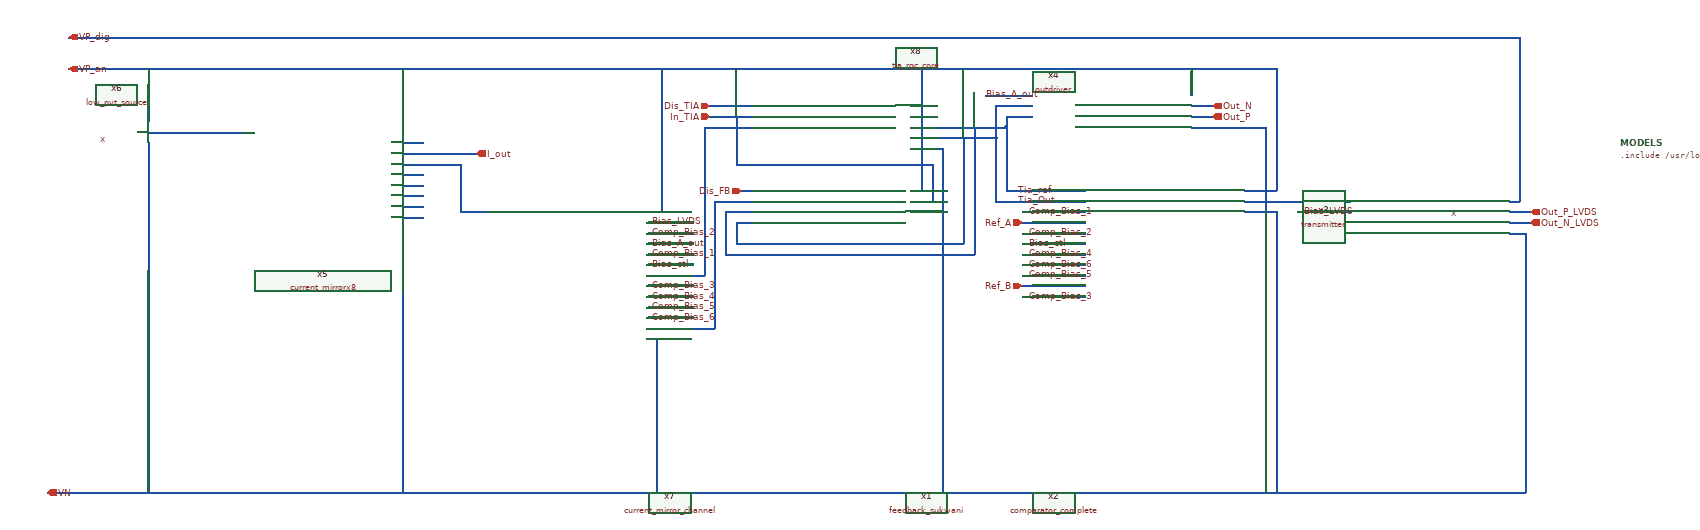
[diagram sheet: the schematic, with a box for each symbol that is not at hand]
v {xschem version=3.0.0 file_version=1.2 }
G {}
K {}
V {}
S {}
E {}
T {x} 180 -630 0 0 0.4 0.4 {}
T {x} 2730 -490 0 0 0.4 0.4 {}
N 80 50 2110 50 { lab=VN}
N 2110 50 2120 50 { lab=VN}
N 120 -750 2120 -750 { lab=VP_an}
N 270 -750 270 -650 { lab=VP_an}
N 750 -750 750 -630 { lab=VP_an}
N 1330 -660 1410 -660 { lab=In_TIA}
N 1350 -640 1410 -640 { lab=#net1}
N 1710 -620 1760 -620 { lab=Tia_Out}
N 1710 -640 1790 -640 { lab=Tia_ref}
N 2240 -680 2280 -680 { lab=Out_N}
N 2240 -660 2280 -660 { lab=Out_P}
N 1710 -660 1750 -660 { lab=#net2}
N 1330 -680 1410 -680 { lab=Dis_TIA}
N 860 -570 860 -500 { lab=#net3}
N 750 -570 860 -570 { lab=#net3}
N 750 -450 750 50 { lab=VN}
N 750 -590 890 -590 { lab=I_out}
N 270 -610 270 50 { lab=VN}
N 270 -630 450 -630 { lab=#net4}
N 750 -610 790 -610 { lab=#net5}
N 750 -550 790 -550 { lab=#net6}
N 750 -530 790 -530 { lab=#net7}
N 750 -510 790 -510 { lab=#net8}
N 750 -490 790 -490 { lab=#net9}
N 750 -470 790 -470 { lab=#net10}
N 1390 -520 1410 -520 { lab=Dis_FB}
N 1240 -750 1240 -500 { lab=VP_an}
N 1230 -180 1230 50 { lab=VN}
N 1710 -600 1770 -600 { lab=VN}
N 1770 -600 1770 50 { lab=VN}
N 1710 -480 1770 -480 { lab=VN}
N 1710 -520 1730 -520 { lab=VP_an}
N 1730 -750 1730 -520 { lab=VP_an}
N 1710 -680 1730 -680 { lab=VP_an}
N 1710 -500 1750 -500 { lab=In_TIA}
N 1750 -570 1750 -500 { lab=In_TIA}
N 1390 -570 1750 -570 { lab=In_TIA}
N 1380 -570 1390 -570 { lab=In_TIA}
N 1380 -660 1380 -570 { lab=In_TIA}
N 1790 -640 1800 -640 { lab=Tia_ref}
N 1920 -660 1940 -660 { lab=Tia_ref}
N 1900 -680 1940 -680 { lab=Tia_Out}
N 1800 -640 1890 -640 { lab=Tia_ref}
N 1890 -640 1890 -520 { lab=Tia_ref}
N 1890 -520 2040 -520 { lab=Tia_ref}
N 1890 -660 1920 -660 { lab=Tia_ref}
N 1890 -660 1890 -640 { lab=Tia_ref}
N 1870 -680 1900 -680 { lab=Tia_Out}
N 1870 -680 1870 -620 { lab=Tia_Out}
N 1760 -620 1870 -620 { lab=Tia_Out}
N 1870 -620 1870 -500 { lab=Tia_Out}
N 1870 -500 2040 -500 { lab=Tia_Out}
N 1360 -480 1410 -480 { lab=Tia_ref}
N 1360 -480 1360 -420 { lab=Tia_ref}
N 1810 -620 1810 -420 { lab=Tia_Out}
N 1380 -460 1410 -460 { lab=Tia_Out}
N 1380 -420 1810 -420 { lab=Tia_Out}
N 1380 -460 1380 -420 { lab=Tia_Out}
N 1360 -420 1360 -410 { lab=Tia_ref}
N 1360 -410 1360 -400 { lab=Tia_ref}
N 1360 -400 1830 -400 { lab=Tia_ref}
N 1830 -640 1830 -400 { lab=Tia_ref}
N 1340 -500 1340 -460 { lab=#net11}
N 1340 -500 1410 -500 { lab=#net11}
N 1320 -640 1320 -440 { lab=#net1}
N 1320 -640 1350 -640 { lab=#net1}
N 1850 -700 1940 -700 { lab=Bias_A_out}
N 1210 -420 1300 -420 { lab=Bias_A_out}
N 1210 -400 1300 -400 { lab=Comp_Bias_1}
N 1210 -380 1300 -380 { lab=Bias_ctl}
N 1210 -360 1300 -360 { lab=#net1}
N 1210 -340 1300 -340 { lab=Comp_Bias_3}
N 1210 -320 1300 -320 { lab=Comp_Bias_4}
N 1210 -280 1300 -280 { lab=Comp_Bias_6}
N 1340 -460 1340 -300 { lab=#net11}
N 1210 -460 1300 -460 { lab=Bias_LVDS}
N 1920 -420 2040 -420 { lab=Bias_ctl}
N 1920 -400 2040 -400 { lab=Comp_Bias_4}
N 1920 -380 2040 -380 { lab=Comp_Bias_6}
N 1920 -360 2040 -360 { lab=Comp_Bias_5}
N 1920 -340 2040 -340 { lab=Ref_B}
N 1920 -320 2040 -320 { lab=Comp_Bias_3}
N 1920 -440 2040 -440 { lab=Comp_Bias_2}
N 1920 -460 2040 -460 { lab=Ref_A}
N 1920 -480 2040 -480 { lab=Comp_Bias_1}
N 1230 -220 1230 -180 { lab=VN}
N 2340 -520 2400 -520 { lab=VP_an}
N 2400 -750 2400 -520 { lab=VP_an}
N 2120 -750 2400 -750 { lab=VP_an}
N 2340 -480 2400 -480 { lab=VN}
N 2400 -480 2400 50 { lab=VN}
N 2120 50 2870 50 { lab=VN}
N 2840 -440 2870 -440 { lab=VN}
N 2870 -440 2870 50 { lab=VN}
N 2860 -750 2860 -500 { lab=VP_dig}
N 2840 -500 2860 -500 { lab=VP_dig}
N 2840 -480 2880 -480 { lab=Out_P_LVDS}
N 2840 -460 2880 -460 { lab=Out_N_LVDS}
N 2440 -480 2540 -480 { lab=Bias_LVDS}
N 2420 -500 2540 -500 { lab=#net12}
N 2340 -500 2420 -500 { lab=#net12}
N 1320 -440 1320 -380 { lab=#net1}
N 1210 -440 1300 -440 { lab=Comp_Bias_2}
N 120 -810 2860 -810 { lab=VP_dig}
N 2860 -810 2860 -750 { lab=VP_dig}
N 1210 -240 1230 -240 { lab=VN}
N 1230 -240 1230 -220 { lab=VN}
N 1210 -260 1340 -260 { lab=#net11}
N 1340 -300 1340 -260 { lab=#net11}
N 1210 -300 1300 -300 { lab=Comp_Bias_5}
N 1300 -360 1320 -360 { lab=#net1}
N 1320 -380 1320 -360 { lab=#net1}
N 1210 -480 1240 -480 { lab=VP_an}
N 1240 -500 1240 -480 { lab=VP_an}
N 860 -480 910 -480 { lab=#net3}
N 860 -500 860 -480 { lab=#net3}
N 2240 -750 2240 -700 { lab=VP_an}
N 2240 -640 2380 -640 { lab=VN}
N 2380 -640 2380 -480 { lab=VN}
C {outdriver/outdriver.sym} 2090 -670 0 0 {name=x4}
C {bias/current_mirrorx8.sym} 600 -540 0 0 {name=x5}
C {bias/low_pvt_source.sym} 120 -630 0 0 {name=x6}
C {bias/current_mirror_channel.sym} 1060 -360 0 0 {name=x7}
C {tia/tia_rgc_core.sym} 1560 -640 0 0 {name=x8}
C {devices/iopin.sym} 120 -750 0 1 {name=p1 lab=VP_an}
C {devices/ipin.sym} 1330 -660 0 0 {name=p2 lab=In_TIA}
C {devices/opin.sym} 2280 -680 0 0 {name=p3 lab=Out_N}
C {devices/iopin.sym} 80 50 0 1 {name=p4 lab=VN}
C {devices/opin.sym} 2280 -660 0 0 {name=p5 lab=Out_P}
C {devices/noconn.sym} 1750 -660 2 0 {name=l2}
C {devices/ipin.sym} 1330 -680 0 0 {name=p6 lab=Dis_TIA}
C {devices/opin.sym} 890 -590 0 0 {name=p7 lab=I_out}
C {devices/noconn.sym} 790 -610 2 0 {name=l3}
C {devices/noconn.sym} 790 -550 2 0 {name=l4}
C {devices/noconn.sym} 790 -530 2 0 {name=l5}
C {devices/noconn.sym} 790 -510 2 0 {name=l6}
C {devices/noconn.sym} 790 -490 2 0 {name=l7}
C {devices/noconn.sym} 790 -470 2 0 {name=l8}
C {tia/feedback_sukwani.sym} 1560 -490 0 0 {name=x1}
C {lvds/transmitter.sym} 2690 -470 0 0 {name=x3}
C {devices/ipin.sym} 1390 -520 0 0 {name=p8 lab=Dis_FB}
C {comp/comparator_complete.sym} 2190 -420 0 0 {name=x2}
C {devices/ipin.sym} 1920 -340 0 0 {name=p9 lab=Ref_B}
C {devices/ipin.sym} 1920 -460 0 0 {name=p10 lab=Ref_A}
C {devices/lab_wire.sym} 1220 -400 0 1 {name=l1 sig_type=std_logic lab=Comp_Bias_1}
C {devices/lab_wire.sym} 1930 -380 0 1 {name=l9 sig_type=std_logic lab=Comp_Bias_6}
C {devices/lab_wire.sym} 1930 -360 0 1 {name=l10 sig_type=std_logic lab=Comp_Bias_5}
C {devices/lab_wire.sym} 1930 -400 0 1 {name=l11 sig_type=std_logic lab=Comp_Bias_4}
C {devices/lab_wire.sym} 1930 -420 0 1 {name=l12 sig_type=std_logic lab=Bias_ctl}
C {devices/lab_wire.sym} 1930 -440 0 1 {name=l13 sig_type=std_logic lab=Comp_Bias_2}
C {devices/lab_wire.sym} 1930 -480 0 1 {name=l14 sig_type=std_logic lab=Comp_Bias_1}
C {devices/lab_wire.sym} 1930 -320 0 1 {name=l15 sig_type=std_logic lab=Comp_Bias_3}
C {devices/lab_wire.sym} 1220 -300 0 1 {name=l16 sig_type=std_logic lab=Comp_Bias_5}
C {devices/lab_wire.sym} 1220 -440 0 1 {name=l17 sig_type=std_logic lab=Comp_Bias_2}
C {devices/lab_wire.sym} 1220 -340 0 1 {name=l18 sig_type=std_logic lab=Comp_Bias_3}
C {devices/lab_wire.sym} 1220 -320 0 1 {name=l19 sig_type=std_logic lab=Comp_Bias_4}
C {devices/lab_wire.sym} 1220 -280 0 1 {name=l20 sig_type=std_logic lab=Comp_Bias_6}
C {devices/opin.sym} 2880 -460 0 0 {name=p11 lab=Out_N_LVDS}
C {devices/opin.sym} 2880 -480 0 0 {name=p12 lab=Out_P_LVDS}
C {devices/lab_wire.sym} 1220 -460 0 1 {name=l22 sig_type=std_logic lab=Bias_LVDS}
C {devices/lab_wire.sym} 2450 -480 0 1 {name=l23 sig_type=std_logic lab=Bias_LVDS}
C {devices/lab_wire.sym} 1220 -380 0 1 {name=l24 sig_type=std_logic lab=Bias_ctl}
C {devices/lab_wire.sym} 1220 -420 0 1 {name=l26 sig_type=std_logic lab=Bias_A_out}
C {devices/lab_wire.sym} 1850 -700 0 1 {name=l27 sig_type=std_logic lab=Bias_A_out}
C {devices/iopin.sym} 120 -810 0 1 {name=p13 lab=VP_dig}
C {devices/lab_wire.sym} 1910 -520 0 1 {name=l21 sig_type=std_logic lab=Tia_ref}
C {devices/lab_wire.sym} 1910 -500 0 1 {name=l25 sig_type=std_logic lab=Tia_Out}
C {devices/code.sym} 3050 -610 0 0 {name=MODELS
only_toplevel=true
format="tcleval( @value )"
value="

.include /usr/local/share/pdk/sky130A/libs.ref/sky130_fd_sc_hs/spice/sky130_fd_sc_hs.spice

"}
